VERSION 5.7 ;
  NOWIREEXTENSIONATPIN ON ;
  DIVIDERCHAR "/" ;
  BUSBITCHARS "[]" ;
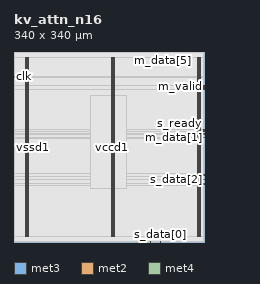
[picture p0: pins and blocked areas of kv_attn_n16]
MACRO kv_attn_n16
  CLASS BLOCK ;
  FOREIGN kv_attn_n16 ;
  ORIGIN 0.000 0.000 ;
  SIZE 340.000 BY 340.000 ;
  PIN clk
    DIRECTION INPUT ;
    USE SIGNAL ;
    ANTENNAGATEAREA 1.286700 ;
    ANTENNADIFFAREA 0.434700 ;
    PORT
      LAYER met3 ;
        RECT 0.000 295.160 0.600 295.760 ;
    END
  END clk
  PIN m_data[0]
    DIRECTION OUTPUT ;
    USE SIGNAL ;
    ANTENNADIFFAREA 0.702900 ;
    PORT
      LAYER met3 ;
        RECT 339.400 278.840 340.000 279.440 ;
    END
  END m_data[0]
  PIN m_data[1]
    DIRECTION OUTPUT ;
    USE SIGNAL ;
    ANTENNADIFFAREA 0.702900 ;
    PORT
      LAYER met3 ;
        RECT 339.400 186.360 340.000 186.960 ;
    END
  END m_data[1]
  PIN m_data[2]
    DIRECTION OUTPUT ;
    USE SIGNAL ;
    ANTENNADIFFAREA 0.702900 ;
    PORT
      LAYER met3 ;
        RECT 339.400 276.120 340.000 276.720 ;
    END
  END m_data[2]
  PIN m_data[3]
    DIRECTION OUTPUT ;
    USE SIGNAL ;
    ANTENNADIFFAREA 0.702900 ;
    PORT
      LAYER met2 ;
        RECT 264.130 339.720 264.410 340.000 ;
    END
  END m_data[3]
  PIN m_data[4]
    DIRECTION OUTPUT ;
    USE SIGNAL ;
    ANTENNADIFFAREA 0.702900 ;
    PORT
      LAYER met2 ;
        RECT 231.930 339.720 232.210 340.000 ;
    END
  END m_data[4]
  PIN m_data[5]
    DIRECTION OUTPUT ;
    USE SIGNAL ;
    ANTENNADIFFAREA 0.702900 ;
    PORT
      LAYER met2 ;
        RECT 265.970 339.720 266.250 340.000 ;
    END
  END m_data[5]
  PIN m_data[6]
    DIRECTION OUTPUT ;
    USE SIGNAL ;
    ANTENNADIFFAREA 0.702900 ;
    PORT
      LAYER met2 ;
        RECT 269.650 339.720 269.930 340.000 ;
    END
  END m_data[6]
  PIN m_data[7]
    DIRECTION OUTPUT ;
    USE SIGNAL ;
    ANTENNADIFFAREA 0.702900 ;
    PORT
      LAYER met2 ;
        RECT 251.250 339.720 251.530 340.000 ;
    END
  END m_data[7]
  PIN m_last
    DIRECTION OUTPUT ;
    USE SIGNAL ;
    ANTENNADIFFAREA 0.702900 ;
    PORT
      LAYER met3 ;
        RECT 339.400 273.400 340.000 274.000 ;
    END
  END m_last
  PIN m_ready
    DIRECTION INPUT ;
    USE SIGNAL ;
    ANTENNAGATEAREA 0.647700 ;
    ANTENNADIFFAREA 0.434700 ;
    PORT
      LAYER met3 ;
        RECT 339.400 274.760 340.000 275.360 ;
    END
  END m_ready
  PIN m_valid
    DIRECTION OUTPUT ;
    USE SIGNAL ;
    ANTENNADIFFAREA 0.702900 ;
    PORT
      LAYER met3 ;
        RECT 339.400 277.480 340.000 278.080 ;
    END
  END m_valid
  PIN rst
    DIRECTION INPUT ;
    USE SIGNAL ;
    ANTENNAGATEAREA 0.647700 ;
    ANTENNADIFFAREA 0.434700 ;
    PORT
      LAYER met3 ;
        RECT 339.400 121.080 340.000 121.680 ;
    END
  END rst
  PIN s_data[0]
    DIRECTION INPUT ;
    USE SIGNAL ;
    ANTENNAGATEAREA 0.647700 ;
    ANTENNADIFFAREA 0.434700 ;
    PORT
      LAYER met2 ;
        RECT 262.290 0.000 262.570 0.280 ;
    END
  END s_data[0]
  PIN s_data[1]
    DIRECTION INPUT ;
    USE SIGNAL ;
    ANTENNAGATEAREA 0.647700 ;
    ANTENNADIFFAREA 0.434700 ;
    PORT
      LAYER met2 ;
        RECT 244.810 0.000 245.090 0.280 ;
    END
  END s_data[1]
  PIN s_data[2]
    DIRECTION INPUT ;
    USE SIGNAL ;
    ANTENNAGATEAREA 0.647700 ;
    ANTENNADIFFAREA 0.434700 ;
    PORT
      LAYER met3 ;
        RECT 339.400 111.560 340.000 112.160 ;
    END
  END s_data[2]
  PIN s_data[3]
    DIRECTION INPUT ;
    USE SIGNAL ;
    ANTENNAGATEAREA 0.647700 ;
    ANTENNADIFFAREA 0.434700 ;
    PORT
      LAYER met2 ;
        RECT 243.890 0.000 244.170 0.280 ;
    END
  END s_data[3]
  PIN s_data[4]
    DIRECTION INPUT ;
    USE SIGNAL ;
    ANTENNAGATEAREA 0.647700 ;
    ANTENNADIFFAREA 0.434700 ;
    PORT
      LAYER met3 ;
        RECT 339.400 118.360 340.000 118.960 ;
    END
  END s_data[4]
  PIN s_data[5]
    DIRECTION INPUT ;
    USE SIGNAL ;
    ANTENNAGATEAREA 0.647700 ;
    ANTENNADIFFAREA 0.434700 ;
    PORT
      LAYER met3 ;
        RECT 339.400 119.720 340.000 120.320 ;
    END
  END s_data[5]
  PIN s_data[6]
    DIRECTION INPUT ;
    USE SIGNAL ;
    ANTENNAGATEAREA 0.647700 ;
    ANTENNADIFFAREA 0.434700 ;
    PORT
      LAYER met3 ;
        RECT 339.400 102.040 340.000 102.640 ;
    END
  END s_data[6]
  PIN s_data[7]
    DIRECTION INPUT ;
    USE SIGNAL ;
    ANTENNAGATEAREA 0.647700 ;
    ANTENNADIFFAREA 0.434700 ;
    PORT
      LAYER met3 ;
        RECT 339.400 103.400 340.000 104.000 ;
    END
  END s_data[7]
  PIN s_last
    DIRECTION INPUT ;
    USE SIGNAL ;
    ANTENNAGATEAREA 0.647700 ;
    ANTENNADIFFAREA 0.434700 ;
    PORT
      LAYER met3 ;
        RECT 339.400 193.160 340.000 193.760 ;
    END
  END s_last
  PIN s_ready
    DIRECTION OUTPUT ;
    USE SIGNAL ;
    ANTENNADIFFAREA 0.702900 ;
    PORT
      LAYER met3 ;
        RECT 339.400 198.600 340.000 199.200 ;
    END
  END s_ready
  PIN s_valid
    DIRECTION INPUT ;
    USE SIGNAL ;
    ANTENNAGATEAREA 0.647700 ;
    ANTENNADIFFAREA 0.434700 ;
    PORT
      LAYER met3 ;
        RECT 339.400 199.960 340.000 200.560 ;
    END
  END s_valid
  PIN vccd1
    DIRECTION INOUT ;
    USE POWER ;
    PORT
      LAYER met4 ;
        RECT 21.040 10.640 22.640 329.360 ;
    END
    PORT
      LAYER met4 ;
        RECT 174.640 10.640 176.240 329.360 ;
    END
    PORT
      LAYER met4 ;
        RECT 328.240 10.640 329.840 329.360 ;
    END
  END vccd1
  PIN vssd1
    DIRECTION INOUT ;
    USE GROUND ;
    PORT
      LAYER met4 ;
        RECT 24.340 10.640 25.940 329.360 ;
    END
    PORT
      LAYER met4 ;
        RECT 177.940 10.640 179.540 329.360 ;
    END
    PORT
      LAYER met4 ;
        RECT 331.540 10.640 333.140 329.360 ;
    END
  END vssd1
  OBS
      LAYER nwell ;
        RECT 5.330 10.795 334.610 329.310 ;
      LAYER li1 ;
        RECT 5.520 10.795 334.420 329.205 ;
      LAYER met1 ;
        RECT 5.520 10.640 338.490 329.360 ;
      LAYER met2 ;
        RECT 0.550 339.440 231.650 339.720 ;
        RECT 232.490 339.440 250.970 339.720 ;
        RECT 251.810 339.440 263.850 339.720 ;
        RECT 264.690 339.440 265.690 339.720 ;
        RECT 266.530 339.440 269.370 339.720 ;
        RECT 270.210 339.440 338.470 339.720 ;
        RECT 0.550 0.560 338.470 339.440 ;
        RECT 0.550 0.280 243.610 0.560 ;
        RECT 244.450 0.280 244.530 0.560 ;
        RECT 245.370 0.280 262.010 0.560 ;
        RECT 262.850 0.280 338.470 0.560 ;
      LAYER met3 ;
        RECT 0.525 296.160 339.400 329.285 ;
        RECT 1.000 294.760 339.400 296.160 ;
        RECT 0.525 279.840 339.400 294.760 ;
        RECT 0.525 273.000 339.000 279.840 ;
        RECT 0.525 200.960 339.400 273.000 ;
        RECT 0.525 198.200 339.000 200.960 ;
        RECT 0.525 194.160 339.400 198.200 ;
        RECT 0.525 192.760 339.000 194.160 ;
        RECT 0.525 187.360 339.400 192.760 ;
        RECT 0.525 185.960 339.000 187.360 ;
        RECT 0.525 122.080 339.400 185.960 ;
        RECT 0.525 117.960 339.000 122.080 ;
        RECT 0.525 112.560 339.400 117.960 ;
        RECT 0.525 111.160 339.000 112.560 ;
        RECT 0.525 104.400 339.400 111.160 ;
        RECT 0.525 101.640 339.000 104.400 ;
        RECT 0.525 10.715 339.400 101.640 ;
      LAYER met4 ;
        RECT 136.455 96.055 174.240 262.985 ;
        RECT 176.640 96.055 177.540 262.985 ;
        RECT 179.940 96.055 201.185 262.985 ;
  END
END kv_attn_n16
END LIBRARY

